VERSION 5.7 ;
BUSBITCHARS "[]" ;
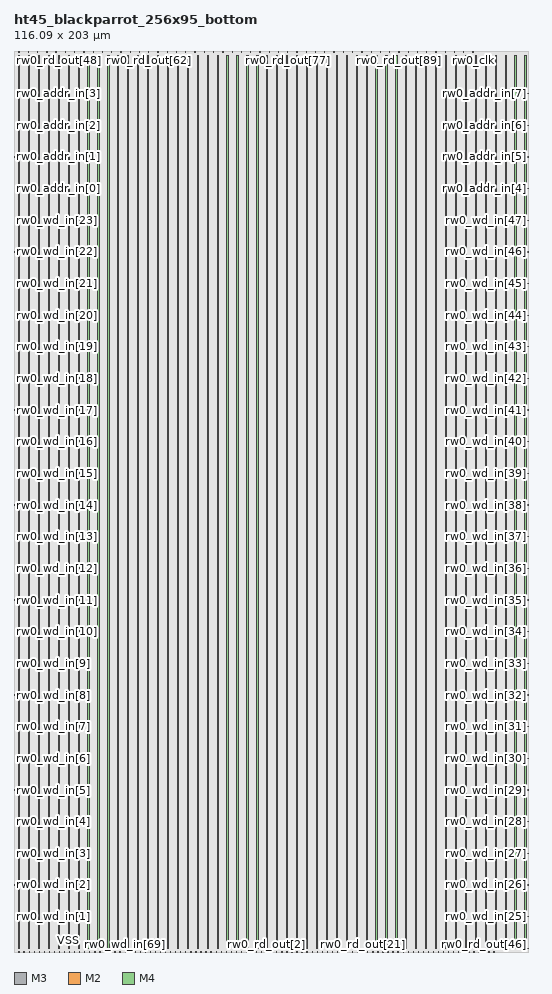
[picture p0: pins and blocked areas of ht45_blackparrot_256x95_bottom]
MACRO ht45_blackparrot_256x95_bottom
  FOREIGN ht45_blackparrot_256x95_bottom 0 0 ;
  SYMMETRY X Y R90 ;
  SIZE 116.090 BY 203.000 ;
  CLASS COVER ;
  PIN rw0_wd_in[0]
    DIRECTION INPUT ;
    USE SIGNAL ;
    SHAPE ABUTMENT ;
    PORT
      LAYER M3 ;
      RECT 0.000 0.805 0.210 0.875 ;
    END
  END rw0_wd_in[0]
  PIN rw0_wd_in[1]
    DIRECTION INPUT ;
    USE SIGNAL ;
    SHAPE ABUTMENT ;
    PORT
      LAYER M3 ;
      RECT 0.000 7.945 0.210 8.015 ;
    END
  END rw0_wd_in[1]
  PIN rw0_wd_in[2]
    DIRECTION INPUT ;
    USE SIGNAL ;
    SHAPE ABUTMENT ;
    PORT
      LAYER M3 ;
      RECT 0.000 15.085 0.210 15.155 ;
    END
  END rw0_wd_in[2]
  PIN rw0_wd_in[3]
    DIRECTION INPUT ;
    USE SIGNAL ;
    SHAPE ABUTMENT ;
    PORT
      LAYER M3 ;
      RECT 0.000 22.225 0.210 22.295 ;
    END
  END rw0_wd_in[3]
  PIN rw0_wd_in[4]
    DIRECTION INPUT ;
    USE SIGNAL ;
    SHAPE ABUTMENT ;
    PORT
      LAYER M3 ;
      RECT 0.000 29.365 0.210 29.435 ;
    END
  END rw0_wd_in[4]
  PIN rw0_wd_in[5]
    DIRECTION INPUT ;
    USE SIGNAL ;
    SHAPE ABUTMENT ;
    PORT
      LAYER M3 ;
      RECT 0.000 36.505 0.210 36.575 ;
    END
  END rw0_wd_in[5]
  PIN rw0_wd_in[6]
    DIRECTION INPUT ;
    USE SIGNAL ;
    SHAPE ABUTMENT ;
    PORT
      LAYER M3 ;
      RECT 0.000 43.645 0.210 43.715 ;
    END
  END rw0_wd_in[6]
  PIN rw0_wd_in[7]
    DIRECTION INPUT ;
    USE SIGNAL ;
    SHAPE ABUTMENT ;
    PORT
      LAYER M3 ;
      RECT 0.000 50.785 0.210 50.855 ;
    END
  END rw0_wd_in[7]
  PIN rw0_wd_in[8]
    DIRECTION INPUT ;
    USE SIGNAL ;
    SHAPE ABUTMENT ;
    PORT
      LAYER M3 ;
      RECT 0.000 57.925 0.210 57.995 ;
    END
  END rw0_wd_in[8]
  PIN rw0_wd_in[9]
    DIRECTION INPUT ;
    USE SIGNAL ;
    SHAPE ABUTMENT ;
    PORT
      LAYER M3 ;
      RECT 0.000 65.065 0.210 65.135 ;
    END
  END rw0_wd_in[9]
  PIN rw0_wd_in[10]
    DIRECTION INPUT ;
    USE SIGNAL ;
    SHAPE ABUTMENT ;
    PORT
      LAYER M3 ;
      RECT 0.000 72.205 0.210 72.275 ;
    END
  END rw0_wd_in[10]
  PIN rw0_wd_in[11]
    DIRECTION INPUT ;
    USE SIGNAL ;
    SHAPE ABUTMENT ;
    PORT
      LAYER M3 ;
      RECT 0.000 79.345 0.210 79.415 ;
    END
  END rw0_wd_in[11]
  PIN rw0_wd_in[12]
    DIRECTION INPUT ;
    USE SIGNAL ;
    SHAPE ABUTMENT ;
    PORT
      LAYER M3 ;
      RECT 0.000 86.485 0.210 86.555 ;
    END
  END rw0_wd_in[12]
  PIN rw0_wd_in[13]
    DIRECTION INPUT ;
    USE SIGNAL ;
    SHAPE ABUTMENT ;
    PORT
      LAYER M3 ;
      RECT 0.000 93.625 0.210 93.695 ;
    END
  END rw0_wd_in[13]
  PIN rw0_wd_in[14]
    DIRECTION INPUT ;
    USE SIGNAL ;
    SHAPE ABUTMENT ;
    PORT
      LAYER M3 ;
      RECT 0.000 100.765 0.210 100.835 ;
    END
  END rw0_wd_in[14]
  PIN rw0_wd_in[15]
    DIRECTION INPUT ;
    USE SIGNAL ;
    SHAPE ABUTMENT ;
    PORT
      LAYER M3 ;
      RECT 0.000 107.905 0.210 107.975 ;
    END
  END rw0_wd_in[15]
  PIN rw0_wd_in[16]
    DIRECTION INPUT ;
    USE SIGNAL ;
    SHAPE ABUTMENT ;
    PORT
      LAYER M3 ;
      RECT 0.000 115.045 0.210 115.115 ;
    END
  END rw0_wd_in[16]
  PIN rw0_wd_in[17]
    DIRECTION INPUT ;
    USE SIGNAL ;
    SHAPE ABUTMENT ;
    PORT
      LAYER M3 ;
      RECT 0.000 122.185 0.210 122.255 ;
    END
  END rw0_wd_in[17]
  PIN rw0_wd_in[18]
    DIRECTION INPUT ;
    USE SIGNAL ;
    SHAPE ABUTMENT ;
    PORT
      LAYER M3 ;
      RECT 0.000 129.325 0.210 129.395 ;
    END
  END rw0_wd_in[18]
  PIN rw0_wd_in[19]
    DIRECTION INPUT ;
    USE SIGNAL ;
    SHAPE ABUTMENT ;
    PORT
      LAYER M3 ;
      RECT 0.000 136.465 0.210 136.535 ;
    END
  END rw0_wd_in[19]
  PIN rw0_wd_in[20]
    DIRECTION INPUT ;
    USE SIGNAL ;
    SHAPE ABUTMENT ;
    PORT
      LAYER M3 ;
      RECT 0.000 143.605 0.210 143.675 ;
    END
  END rw0_wd_in[20]
  PIN rw0_wd_in[21]
    DIRECTION INPUT ;
    USE SIGNAL ;
    SHAPE ABUTMENT ;
    PORT
      LAYER M3 ;
      RECT 0.000 150.745 0.210 150.815 ;
    END
  END rw0_wd_in[21]
  PIN rw0_wd_in[22]
    DIRECTION INPUT ;
    USE SIGNAL ;
    SHAPE ABUTMENT ;
    PORT
      LAYER M3 ;
      RECT 0.000 157.885 0.210 157.955 ;
    END
  END rw0_wd_in[22]
  PIN rw0_wd_in[23]
    DIRECTION INPUT ;
    USE SIGNAL ;
    SHAPE ABUTMENT ;
    PORT
      LAYER M3 ;
      RECT 0.000 165.025 0.210 165.095 ;
    END
  END rw0_wd_in[23]
  PIN rw0_wd_in[24]
    DIRECTION INPUT ;
    USE SIGNAL ;
    SHAPE ABUTMENT ;
    PORT
      LAYER M3 ;
      RECT 115.880 0.805 116.090 0.875 ;
    END
  END rw0_wd_in[24]
  PIN rw0_wd_in[25]
    DIRECTION INPUT ;
    USE SIGNAL ;
    SHAPE ABUTMENT ;
    PORT
      LAYER M3 ;
      RECT 115.880 7.945 116.090 8.015 ;
    END
  END rw0_wd_in[25]
  PIN rw0_wd_in[26]
    DIRECTION INPUT ;
    USE SIGNAL ;
    SHAPE ABUTMENT ;
    PORT
      LAYER M3 ;
      RECT 115.880 15.085 116.090 15.155 ;
    END
  END rw0_wd_in[26]
  PIN rw0_wd_in[27]
    DIRECTION INPUT ;
    USE SIGNAL ;
    SHAPE ABUTMENT ;
    PORT
      LAYER M3 ;
      RECT 115.880 22.225 116.090 22.295 ;
    END
  END rw0_wd_in[27]
  PIN rw0_wd_in[28]
    DIRECTION INPUT ;
    USE SIGNAL ;
    SHAPE ABUTMENT ;
    PORT
      LAYER M3 ;
      RECT 115.880 29.365 116.090 29.435 ;
    END
  END rw0_wd_in[28]
  PIN rw0_wd_in[29]
    DIRECTION INPUT ;
    USE SIGNAL ;
    SHAPE ABUTMENT ;
    PORT
      LAYER M3 ;
      RECT 115.880 36.505 116.090 36.575 ;
    END
  END rw0_wd_in[29]
  PIN rw0_wd_in[30]
    DIRECTION INPUT ;
    USE SIGNAL ;
    SHAPE ABUTMENT ;
    PORT
      LAYER M3 ;
      RECT 115.880 43.645 116.090 43.715 ;
    END
  END rw0_wd_in[30]
  PIN rw0_wd_in[31]
    DIRECTION INPUT ;
    USE SIGNAL ;
    SHAPE ABUTMENT ;
    PORT
      LAYER M3 ;
      RECT 115.880 50.785 116.090 50.855 ;
    END
  END rw0_wd_in[31]
  PIN rw0_wd_in[32]
    DIRECTION INPUT ;
    USE SIGNAL ;
    SHAPE ABUTMENT ;
    PORT
      LAYER M3 ;
      RECT 115.880 57.925 116.090 57.995 ;
    END
  END rw0_wd_in[32]
  PIN rw0_wd_in[33]
    DIRECTION INPUT ;
    USE SIGNAL ;
    SHAPE ABUTMENT ;
    PORT
      LAYER M3 ;
      RECT 115.880 65.065 116.090 65.135 ;
    END
  END rw0_wd_in[33]
  PIN rw0_wd_in[34]
    DIRECTION INPUT ;
    USE SIGNAL ;
    SHAPE ABUTMENT ;
    PORT
      LAYER M3 ;
      RECT 115.880 72.205 116.090 72.275 ;
    END
  END rw0_wd_in[34]
  PIN rw0_wd_in[35]
    DIRECTION INPUT ;
    USE SIGNAL ;
    SHAPE ABUTMENT ;
    PORT
      LAYER M3 ;
      RECT 115.880 79.345 116.090 79.415 ;
    END
  END rw0_wd_in[35]
  PIN rw0_wd_in[36]
    DIRECTION INPUT ;
    USE SIGNAL ;
    SHAPE ABUTMENT ;
    PORT
      LAYER M3 ;
      RECT 115.880 86.485 116.090 86.555 ;
    END
  END rw0_wd_in[36]
  PIN rw0_wd_in[37]
    DIRECTION INPUT ;
    USE SIGNAL ;
    SHAPE ABUTMENT ;
    PORT
      LAYER M3 ;
      RECT 115.880 93.625 116.090 93.695 ;
    END
  END rw0_wd_in[37]
  PIN rw0_wd_in[38]
    DIRECTION INPUT ;
    USE SIGNAL ;
    SHAPE ABUTMENT ;
    PORT
      LAYER M3 ;
      RECT 115.880 100.765 116.090 100.835 ;
    END
  END rw0_wd_in[38]
  PIN rw0_wd_in[39]
    DIRECTION INPUT ;
    USE SIGNAL ;
    SHAPE ABUTMENT ;
    PORT
      LAYER M3 ;
      RECT 115.880 107.905 116.090 107.975 ;
    END
  END rw0_wd_in[39]
  PIN rw0_wd_in[40]
    DIRECTION INPUT ;
    USE SIGNAL ;
    SHAPE ABUTMENT ;
    PORT
      LAYER M3 ;
      RECT 115.880 115.045 116.090 115.115 ;
    END
  END rw0_wd_in[40]
  PIN rw0_wd_in[41]
    DIRECTION INPUT ;
    USE SIGNAL ;
    SHAPE ABUTMENT ;
    PORT
      LAYER M3 ;
      RECT 115.880 122.185 116.090 122.255 ;
    END
  END rw0_wd_in[41]
  PIN rw0_wd_in[42]
    DIRECTION INPUT ;
    USE SIGNAL ;
    SHAPE ABUTMENT ;
    PORT
      LAYER M3 ;
      RECT 115.880 129.325 116.090 129.395 ;
    END
  END rw0_wd_in[42]
  PIN rw0_wd_in[43]
    DIRECTION INPUT ;
    USE SIGNAL ;
    SHAPE ABUTMENT ;
    PORT
      LAYER M3 ;
      RECT 115.880 136.465 116.090 136.535 ;
    END
  END rw0_wd_in[43]
  PIN rw0_wd_in[44]
    DIRECTION INPUT ;
    USE SIGNAL ;
    SHAPE ABUTMENT ;
    PORT
      LAYER M3 ;
      RECT 115.880 143.605 116.090 143.675 ;
    END
  END rw0_wd_in[44]
  PIN rw0_wd_in[45]
    DIRECTION INPUT ;
    USE SIGNAL ;
    SHAPE ABUTMENT ;
    PORT
      LAYER M3 ;
      RECT 115.880 150.745 116.090 150.815 ;
    END
  END rw0_wd_in[45]
  PIN rw0_wd_in[46]
    DIRECTION INPUT ;
    USE SIGNAL ;
    SHAPE ABUTMENT ;
    PORT
      LAYER M3 ;
      RECT 115.880 157.885 116.090 157.955 ;
    END
  END rw0_wd_in[46]
  PIN rw0_wd_in[47]
    DIRECTION INPUT ;
    USE SIGNAL ;
    SHAPE ABUTMENT ;
    PORT
      LAYER M3 ;
      RECT 115.880 165.025 116.090 165.095 ;
    END
  END rw0_wd_in[47]
  PIN rw0_wd_in[48]
    DIRECTION INPUT ;
    USE SIGNAL ;
    SHAPE ABUTMENT ;
    PORT
      LAYER M2 ;
      RECT 1.105 0.000 1.175 0.210 ;
    END
  END rw0_wd_in[48]
  PIN rw0_wd_in[49]
    DIRECTION INPUT ;
    USE SIGNAL ;
    SHAPE ABUTMENT ;
    PORT
      LAYER M2 ;
      RECT 2.245 0.000 2.315 0.210 ;
    END
  END rw0_wd_in[49]
  PIN rw0_wd_in[50]
    DIRECTION INPUT ;
    USE SIGNAL ;
    SHAPE ABUTMENT ;
    PORT
      LAYER M2 ;
      RECT 3.385 0.000 3.455 0.210 ;
    END
  END rw0_wd_in[50]
  PIN rw0_wd_in[51]
    DIRECTION INPUT ;
    USE SIGNAL ;
    SHAPE ABUTMENT ;
    PORT
      LAYER M2 ;
      RECT 4.525 0.000 4.595 0.210 ;
    END
  END rw0_wd_in[51]
  PIN rw0_wd_in[52]
    DIRECTION INPUT ;
    USE SIGNAL ;
    SHAPE ABUTMENT ;
    PORT
      LAYER M2 ;
      RECT 5.665 0.000 5.735 0.210 ;
    END
  END rw0_wd_in[52]
  PIN rw0_wd_in[53]
    DIRECTION INPUT ;
    USE SIGNAL ;
    SHAPE ABUTMENT ;
    PORT
      LAYER M2 ;
      RECT 6.805 0.000 6.875 0.210 ;
    END
  END rw0_wd_in[53]
  PIN rw0_wd_in[54]
    DIRECTION INPUT ;
    USE SIGNAL ;
    SHAPE ABUTMENT ;
    PORT
      LAYER M2 ;
      RECT 7.945 0.000 8.015 0.210 ;
    END
  END rw0_wd_in[54]
  PIN rw0_wd_in[55]
    DIRECTION INPUT ;
    USE SIGNAL ;
    SHAPE ABUTMENT ;
    PORT
      LAYER M2 ;
      RECT 9.085 0.000 9.155 0.210 ;
    END
  END rw0_wd_in[55]
  PIN rw0_wd_in[56]
    DIRECTION INPUT ;
    USE SIGNAL ;
    SHAPE ABUTMENT ;
    PORT
      LAYER M2 ;
      RECT 10.225 0.000 10.295 0.210 ;
    END
  END rw0_wd_in[56]
  PIN rw0_wd_in[57]
    DIRECTION INPUT ;
    USE SIGNAL ;
    SHAPE ABUTMENT ;
    PORT
      LAYER M2 ;
      RECT 11.365 0.000 11.435 0.210 ;
    END
  END rw0_wd_in[57]
  PIN rw0_wd_in[58]
    DIRECTION INPUT ;
    USE SIGNAL ;
    SHAPE ABUTMENT ;
    PORT
      LAYER M2 ;
      RECT 12.505 0.000 12.575 0.210 ;
    END
  END rw0_wd_in[58]
  PIN rw0_wd_in[59]
    DIRECTION INPUT ;
    USE SIGNAL ;
    SHAPE ABUTMENT ;
    PORT
      LAYER M2 ;
      RECT 13.645 0.000 13.715 0.210 ;
    END
  END rw0_wd_in[59]
  PIN rw0_wd_in[60]
    DIRECTION INPUT ;
    USE SIGNAL ;
    SHAPE ABUTMENT ;
    PORT
      LAYER M2 ;
      RECT 14.785 0.000 14.855 0.210 ;
    END
  END rw0_wd_in[60]
  PIN rw0_wd_in[61]
    DIRECTION INPUT ;
    USE SIGNAL ;
    SHAPE ABUTMENT ;
    PORT
      LAYER M2 ;
      RECT 15.925 0.000 15.995 0.210 ;
    END
  END rw0_wd_in[61]
  PIN rw0_wd_in[62]
    DIRECTION INPUT ;
    USE SIGNAL ;
    SHAPE ABUTMENT ;
    PORT
      LAYER M2 ;
      RECT 17.065 0.000 17.135 0.210 ;
    END
  END rw0_wd_in[62]
  PIN rw0_wd_in[63]
    DIRECTION INPUT ;
    USE SIGNAL ;
    SHAPE ABUTMENT ;
    PORT
      LAYER M2 ;
      RECT 18.205 0.000 18.275 0.210 ;
    END
  END rw0_wd_in[63]
  PIN rw0_wd_in[64]
    DIRECTION INPUT ;
    USE SIGNAL ;
    SHAPE ABUTMENT ;
    PORT
      LAYER M2 ;
      RECT 19.345 0.000 19.415 0.210 ;
    END
  END rw0_wd_in[64]
  PIN rw0_wd_in[65]
    DIRECTION INPUT ;
    USE SIGNAL ;
    SHAPE ABUTMENT ;
    PORT
      LAYER M2 ;
      RECT 20.485 0.000 20.555 0.210 ;
    END
  END rw0_wd_in[65]
  PIN rw0_wd_in[66]
    DIRECTION INPUT ;
    USE SIGNAL ;
    SHAPE ABUTMENT ;
    PORT
      LAYER M2 ;
      RECT 21.625 0.000 21.695 0.210 ;
    END
  END rw0_wd_in[66]
  PIN rw0_wd_in[67]
    DIRECTION INPUT ;
    USE SIGNAL ;
    SHAPE ABUTMENT ;
    PORT
      LAYER M2 ;
      RECT 22.765 0.000 22.835 0.210 ;
    END
  END rw0_wd_in[67]
  PIN rw0_wd_in[68]
    DIRECTION INPUT ;
    USE SIGNAL ;
    SHAPE ABUTMENT ;
    PORT
      LAYER M2 ;
      RECT 23.905 0.000 23.975 0.210 ;
    END
  END rw0_wd_in[68]
  PIN rw0_wd_in[69]
    DIRECTION INPUT ;
    USE SIGNAL ;
    SHAPE ABUTMENT ;
    PORT
      LAYER M2 ;
      RECT 25.045 0.000 25.115 0.210 ;
    END
  END rw0_wd_in[69]
  PIN rw0_wd_in[70]
    DIRECTION INPUT ;
    USE SIGNAL ;
    SHAPE ABUTMENT ;
    PORT
      LAYER M2 ;
      RECT 26.185 0.000 26.255 0.210 ;
    END
  END rw0_wd_in[70]
  PIN rw0_wd_in[71]
    DIRECTION INPUT ;
    USE SIGNAL ;
    SHAPE ABUTMENT ;
    PORT
      LAYER M2 ;
      RECT 27.325 0.000 27.395 0.210 ;
    END
  END rw0_wd_in[71]
  PIN rw0_wd_in[72]
    DIRECTION INPUT ;
    USE SIGNAL ;
    SHAPE ABUTMENT ;
    PORT
      LAYER M2 ;
      RECT 28.465 0.000 28.535 0.210 ;
    END
  END rw0_wd_in[72]
  PIN rw0_wd_in[73]
    DIRECTION INPUT ;
    USE SIGNAL ;
    SHAPE ABUTMENT ;
    PORT
      LAYER M2 ;
      RECT 29.605 0.000 29.675 0.210 ;
    END
  END rw0_wd_in[73]
  PIN rw0_wd_in[74]
    DIRECTION INPUT ;
    USE SIGNAL ;
    SHAPE ABUTMENT ;
    PORT
      LAYER M2 ;
      RECT 30.745 0.000 30.815 0.210 ;
    END
  END rw0_wd_in[74]
  PIN rw0_wd_in[75]
    DIRECTION INPUT ;
    USE SIGNAL ;
    SHAPE ABUTMENT ;
    PORT
      LAYER M2 ;
      RECT 31.885 0.000 31.955 0.210 ;
    END
  END rw0_wd_in[75]
  PIN rw0_wd_in[76]
    DIRECTION INPUT ;
    USE SIGNAL ;
    SHAPE ABUTMENT ;
    PORT
      LAYER M2 ;
      RECT 33.025 0.000 33.095 0.210 ;
    END
  END rw0_wd_in[76]
  PIN rw0_wd_in[77]
    DIRECTION INPUT ;
    USE SIGNAL ;
    SHAPE ABUTMENT ;
    PORT
      LAYER M2 ;
      RECT 34.165 0.000 34.235 0.210 ;
    END
  END rw0_wd_in[77]
  PIN rw0_wd_in[78]
    DIRECTION INPUT ;
    USE SIGNAL ;
    SHAPE ABUTMENT ;
    PORT
      LAYER M2 ;
      RECT 35.305 0.000 35.375 0.210 ;
    END
  END rw0_wd_in[78]
  PIN rw0_wd_in[79]
    DIRECTION INPUT ;
    USE SIGNAL ;
    SHAPE ABUTMENT ;
    PORT
      LAYER M2 ;
      RECT 36.445 0.000 36.515 0.210 ;
    END
  END rw0_wd_in[79]
  PIN rw0_wd_in[80]
    DIRECTION INPUT ;
    USE SIGNAL ;
    SHAPE ABUTMENT ;
    PORT
      LAYER M2 ;
      RECT 37.585 0.000 37.655 0.210 ;
    END
  END rw0_wd_in[80]
  PIN rw0_wd_in[81]
    DIRECTION INPUT ;
    USE SIGNAL ;
    SHAPE ABUTMENT ;
    PORT
      LAYER M2 ;
      RECT 38.725 0.000 38.795 0.210 ;
    END
  END rw0_wd_in[81]
  PIN rw0_wd_in[82]
    DIRECTION INPUT ;
    USE SIGNAL ;
    SHAPE ABUTMENT ;
    PORT
      LAYER M2 ;
      RECT 39.865 0.000 39.935 0.210 ;
    END
  END rw0_wd_in[82]
  PIN rw0_wd_in[83]
    DIRECTION INPUT ;
    USE SIGNAL ;
    SHAPE ABUTMENT ;
    PORT
      LAYER M2 ;
      RECT 41.005 0.000 41.075 0.210 ;
    END
  END rw0_wd_in[83]
  PIN rw0_wd_in[84]
    DIRECTION INPUT ;
    USE SIGNAL ;
    SHAPE ABUTMENT ;
    PORT
      LAYER M2 ;
      RECT 42.145 0.000 42.215 0.210 ;
    END
  END rw0_wd_in[84]
  PIN rw0_wd_in[85]
    DIRECTION INPUT ;
    USE SIGNAL ;
    SHAPE ABUTMENT ;
    PORT
      LAYER M2 ;
      RECT 43.285 0.000 43.355 0.210 ;
    END
  END rw0_wd_in[85]
  PIN rw0_wd_in[86]
    DIRECTION INPUT ;
    USE SIGNAL ;
    SHAPE ABUTMENT ;
    PORT
      LAYER M2 ;
      RECT 44.425 0.000 44.495 0.210 ;
    END
  END rw0_wd_in[86]
  PIN rw0_wd_in[87]
    DIRECTION INPUT ;
    USE SIGNAL ;
    SHAPE ABUTMENT ;
    PORT
      LAYER M2 ;
      RECT 45.565 0.000 45.635 0.210 ;
    END
  END rw0_wd_in[87]
  PIN rw0_wd_in[88]
    DIRECTION INPUT ;
    USE SIGNAL ;
    SHAPE ABUTMENT ;
    PORT
      LAYER M2 ;
      RECT 46.705 0.000 46.775 0.210 ;
    END
  END rw0_wd_in[88]
  PIN rw0_wd_in[89]
    DIRECTION INPUT ;
    USE SIGNAL ;
    SHAPE ABUTMENT ;
    PORT
      LAYER M2 ;
      RECT 47.845 0.000 47.915 0.210 ;
    END
  END rw0_wd_in[89]
  PIN rw0_wd_in[90]
    DIRECTION INPUT ;
    USE SIGNAL ;
    SHAPE ABUTMENT ;
    PORT
      LAYER M2 ;
      RECT 48.985 0.000 49.055 0.210 ;
    END
  END rw0_wd_in[90]
  PIN rw0_wd_in[91]
    DIRECTION INPUT ;
    USE SIGNAL ;
    SHAPE ABUTMENT ;
    PORT
      LAYER M2 ;
      RECT 50.125 0.000 50.195 0.210 ;
    END
  END rw0_wd_in[91]
  PIN rw0_wd_in[92]
    DIRECTION INPUT ;
    USE SIGNAL ;
    SHAPE ABUTMENT ;
    PORT
      LAYER M2 ;
      RECT 51.265 0.000 51.335 0.210 ;
    END
  END rw0_wd_in[92]
  PIN rw0_wd_in[93]
    DIRECTION INPUT ;
    USE SIGNAL ;
    SHAPE ABUTMENT ;
    PORT
      LAYER M2 ;
      RECT 52.405 0.000 52.475 0.210 ;
    END
  END rw0_wd_in[93]
  PIN rw0_wd_in[94]
    DIRECTION INPUT ;
    USE SIGNAL ;
    SHAPE ABUTMENT ;
    PORT
      LAYER M2 ;
      RECT 53.545 0.000 53.615 0.210 ;
    END
  END rw0_wd_in[94]
  PIN rw0_rd_out[0]
    DIRECTION OUTPUT ;
    USE SIGNAL ;
    SHAPE ABUTMENT ;
    PORT
      LAYER M2 ;
      RECT 54.685 0.000 54.755 0.210 ;
    END
  END rw0_rd_out[0]
  PIN rw0_rd_out[1]
    DIRECTION OUTPUT ;
    USE SIGNAL ;
    SHAPE ABUTMENT ;
    PORT
      LAYER M2 ;
      RECT 55.825 0.000 55.895 0.210 ;
    END
  END rw0_rd_out[1]
  PIN rw0_rd_out[2]
    DIRECTION OUTPUT ;
    USE SIGNAL ;
    SHAPE ABUTMENT ;
    PORT
      LAYER M2 ;
      RECT 56.965 0.000 57.035 0.210 ;
    END
  END rw0_rd_out[2]
  PIN rw0_rd_out[3]
    DIRECTION OUTPUT ;
    USE SIGNAL ;
    SHAPE ABUTMENT ;
    PORT
      LAYER M2 ;
      RECT 58.105 0.000 58.175 0.210 ;
    END
  END rw0_rd_out[3]
  PIN rw0_rd_out[4]
    DIRECTION OUTPUT ;
    USE SIGNAL ;
    SHAPE ABUTMENT ;
    PORT
      LAYER M2 ;
      RECT 59.245 0.000 59.315 0.210 ;
    END
  END rw0_rd_out[4]
  PIN rw0_rd_out[5]
    DIRECTION OUTPUT ;
    USE SIGNAL ;
    SHAPE ABUTMENT ;
    PORT
      LAYER M2 ;
      RECT 60.385 0.000 60.455 0.210 ;
    END
  END rw0_rd_out[5]
  PIN rw0_rd_out[6]
    DIRECTION OUTPUT ;
    USE SIGNAL ;
    SHAPE ABUTMENT ;
    PORT
      LAYER M2 ;
      RECT 61.525 0.000 61.595 0.210 ;
    END
  END rw0_rd_out[6]
  PIN rw0_rd_out[7]
    DIRECTION OUTPUT ;
    USE SIGNAL ;
    SHAPE ABUTMENT ;
    PORT
      LAYER M2 ;
      RECT 62.665 0.000 62.735 0.210 ;
    END
  END rw0_rd_out[7]
  PIN rw0_rd_out[8]
    DIRECTION OUTPUT ;
    USE SIGNAL ;
    SHAPE ABUTMENT ;
    PORT
      LAYER M2 ;
      RECT 63.805 0.000 63.875 0.210 ;
    END
  END rw0_rd_out[8]
  PIN rw0_rd_out[9]
    DIRECTION OUTPUT ;
    USE SIGNAL ;
    SHAPE ABUTMENT ;
    PORT
      LAYER M2 ;
      RECT 64.945 0.000 65.015 0.210 ;
    END
  END rw0_rd_out[9]
  PIN rw0_rd_out[10]
    DIRECTION OUTPUT ;
    USE SIGNAL ;
    SHAPE ABUTMENT ;
    PORT
      LAYER M2 ;
      RECT 66.085 0.000 66.155 0.210 ;
    END
  END rw0_rd_out[10]
  PIN rw0_rd_out[11]
    DIRECTION OUTPUT ;
    USE SIGNAL ;
    SHAPE ABUTMENT ;
    PORT
      LAYER M2 ;
      RECT 67.225 0.000 67.295 0.210 ;
    END
  END rw0_rd_out[11]
  PIN rw0_rd_out[12]
    DIRECTION OUTPUT ;
    USE SIGNAL ;
    SHAPE ABUTMENT ;
    PORT
      LAYER M2 ;
      RECT 68.365 0.000 68.435 0.210 ;
    END
  END rw0_rd_out[12]
  PIN rw0_rd_out[13]
    DIRECTION OUTPUT ;
    USE SIGNAL ;
    SHAPE ABUTMENT ;
    PORT
      LAYER M2 ;
      RECT 69.505 0.000 69.575 0.210 ;
    END
  END rw0_rd_out[13]
  PIN rw0_rd_out[14]
    DIRECTION OUTPUT ;
    USE SIGNAL ;
    SHAPE ABUTMENT ;
    PORT
      LAYER M2 ;
      RECT 70.645 0.000 70.715 0.210 ;
    END
  END rw0_rd_out[14]
  PIN rw0_rd_out[15]
    DIRECTION OUTPUT ;
    USE SIGNAL ;
    SHAPE ABUTMENT ;
    PORT
      LAYER M2 ;
      RECT 71.785 0.000 71.855 0.210 ;
    END
  END rw0_rd_out[15]
  PIN rw0_rd_out[16]
    DIRECTION OUTPUT ;
    USE SIGNAL ;
    SHAPE ABUTMENT ;
    PORT
      LAYER M2 ;
      RECT 72.925 0.000 72.995 0.210 ;
    END
  END rw0_rd_out[16]
  PIN rw0_rd_out[17]
    DIRECTION OUTPUT ;
    USE SIGNAL ;
    SHAPE ABUTMENT ;
    PORT
      LAYER M2 ;
      RECT 74.065 0.000 74.135 0.210 ;
    END
  END rw0_rd_out[17]
  PIN rw0_rd_out[18]
    DIRECTION OUTPUT ;
    USE SIGNAL ;
    SHAPE ABUTMENT ;
    PORT
      LAYER M2 ;
      RECT 75.205 0.000 75.275 0.210 ;
    END
  END rw0_rd_out[18]
  PIN rw0_rd_out[19]
    DIRECTION OUTPUT ;
    USE SIGNAL ;
    SHAPE ABUTMENT ;
    PORT
      LAYER M2 ;
      RECT 76.345 0.000 76.415 0.210 ;
    END
  END rw0_rd_out[19]
  PIN rw0_rd_out[20]
    DIRECTION OUTPUT ;
    USE SIGNAL ;
    SHAPE ABUTMENT ;
    PORT
      LAYER M2 ;
      RECT 77.485 0.000 77.555 0.210 ;
    END
  END rw0_rd_out[20]
  PIN rw0_rd_out[21]
    DIRECTION OUTPUT ;
    USE SIGNAL ;
    SHAPE ABUTMENT ;
    PORT
      LAYER M2 ;
      RECT 78.625 0.000 78.695 0.210 ;
    END
  END rw0_rd_out[21]
  PIN rw0_rd_out[22]
    DIRECTION OUTPUT ;
    USE SIGNAL ;
    SHAPE ABUTMENT ;
    PORT
      LAYER M2 ;
      RECT 79.765 0.000 79.835 0.210 ;
    END
  END rw0_rd_out[22]
  PIN rw0_rd_out[23]
    DIRECTION OUTPUT ;
    USE SIGNAL ;
    SHAPE ABUTMENT ;
    PORT
      LAYER M2 ;
      RECT 80.905 0.000 80.975 0.210 ;
    END
  END rw0_rd_out[23]
  PIN rw0_rd_out[24]
    DIRECTION OUTPUT ;
    USE SIGNAL ;
    SHAPE ABUTMENT ;
    PORT
      LAYER M2 ;
      RECT 82.045 0.000 82.115 0.210 ;
    END
  END rw0_rd_out[24]
  PIN rw0_rd_out[25]
    DIRECTION OUTPUT ;
    USE SIGNAL ;
    SHAPE ABUTMENT ;
    PORT
      LAYER M2 ;
      RECT 83.185 0.000 83.255 0.210 ;
    END
  END rw0_rd_out[25]
  PIN rw0_rd_out[26]
    DIRECTION OUTPUT ;
    USE SIGNAL ;
    SHAPE ABUTMENT ;
    PORT
      LAYER M2 ;
      RECT 84.325 0.000 84.395 0.210 ;
    END
  END rw0_rd_out[26]
  PIN rw0_rd_out[27]
    DIRECTION OUTPUT ;
    USE SIGNAL ;
    SHAPE ABUTMENT ;
    PORT
      LAYER M2 ;
      RECT 85.465 0.000 85.535 0.210 ;
    END
  END rw0_rd_out[27]
  PIN rw0_rd_out[28]
    DIRECTION OUTPUT ;
    USE SIGNAL ;
    SHAPE ABUTMENT ;
    PORT
      LAYER M2 ;
      RECT 86.605 0.000 86.675 0.210 ;
    END
  END rw0_rd_out[28]
  PIN rw0_rd_out[29]
    DIRECTION OUTPUT ;
    USE SIGNAL ;
    SHAPE ABUTMENT ;
    PORT
      LAYER M2 ;
      RECT 87.745 0.000 87.815 0.210 ;
    END
  END rw0_rd_out[29]
  PIN rw0_rd_out[30]
    DIRECTION OUTPUT ;
    USE SIGNAL ;
    SHAPE ABUTMENT ;
    PORT
      LAYER M2 ;
      RECT 88.885 0.000 88.955 0.210 ;
    END
  END rw0_rd_out[30]
  PIN rw0_rd_out[31]
    DIRECTION OUTPUT ;
    USE SIGNAL ;
    SHAPE ABUTMENT ;
    PORT
      LAYER M2 ;
      RECT 90.025 0.000 90.095 0.210 ;
    END
  END rw0_rd_out[31]
  PIN rw0_rd_out[32]
    DIRECTION OUTPUT ;
    USE SIGNAL ;
    SHAPE ABUTMENT ;
    PORT
      LAYER M2 ;
      RECT 91.165 0.000 91.235 0.210 ;
    END
  END rw0_rd_out[32]
  PIN rw0_rd_out[33]
    DIRECTION OUTPUT ;
    USE SIGNAL ;
    SHAPE ABUTMENT ;
    PORT
      LAYER M2 ;
      RECT 92.305 0.000 92.375 0.210 ;
    END
  END rw0_rd_out[33]
  PIN rw0_rd_out[34]
    DIRECTION OUTPUT ;
    USE SIGNAL ;
    SHAPE ABUTMENT ;
    PORT
      LAYER M2 ;
      RECT 93.445 0.000 93.515 0.210 ;
    END
  END rw0_rd_out[34]
  PIN rw0_rd_out[35]
    DIRECTION OUTPUT ;
    USE SIGNAL ;
    SHAPE ABUTMENT ;
    PORT
      LAYER M2 ;
      RECT 94.585 0.000 94.655 0.210 ;
    END
  END rw0_rd_out[35]
  PIN rw0_rd_out[36]
    DIRECTION OUTPUT ;
    USE SIGNAL ;
    SHAPE ABUTMENT ;
    PORT
      LAYER M2 ;
      RECT 95.725 0.000 95.795 0.210 ;
    END
  END rw0_rd_out[36]
  PIN rw0_rd_out[37]
    DIRECTION OUTPUT ;
    USE SIGNAL ;
    SHAPE ABUTMENT ;
    PORT
      LAYER M2 ;
      RECT 96.865 0.000 96.935 0.210 ;
    END
  END rw0_rd_out[37]
  PIN rw0_rd_out[38]
    DIRECTION OUTPUT ;
    USE SIGNAL ;
    SHAPE ABUTMENT ;
    PORT
      LAYER M2 ;
      RECT 98.005 0.000 98.075 0.210 ;
    END
  END rw0_rd_out[38]
  PIN rw0_rd_out[39]
    DIRECTION OUTPUT ;
    USE SIGNAL ;
    SHAPE ABUTMENT ;
    PORT
      LAYER M2 ;
      RECT 99.145 0.000 99.215 0.210 ;
    END
  END rw0_rd_out[39]
  PIN rw0_rd_out[40]
    DIRECTION OUTPUT ;
    USE SIGNAL ;
    SHAPE ABUTMENT ;
    PORT
      LAYER M2 ;
      RECT 100.285 0.000 100.355 0.210 ;
    END
  END rw0_rd_out[40]
  PIN rw0_rd_out[41]
    DIRECTION OUTPUT ;
    USE SIGNAL ;
    SHAPE ABUTMENT ;
    PORT
      LAYER M2 ;
      RECT 101.425 0.000 101.495 0.210 ;
    END
  END rw0_rd_out[41]
  PIN rw0_rd_out[42]
    DIRECTION OUTPUT ;
    USE SIGNAL ;
    SHAPE ABUTMENT ;
    PORT
      LAYER M2 ;
      RECT 102.565 0.000 102.635 0.210 ;
    END
  END rw0_rd_out[42]
  PIN rw0_rd_out[43]
    DIRECTION OUTPUT ;
    USE SIGNAL ;
    SHAPE ABUTMENT ;
    PORT
      LAYER M2 ;
      RECT 103.705 0.000 103.775 0.210 ;
    END
  END rw0_rd_out[43]
  PIN rw0_rd_out[44]
    DIRECTION OUTPUT ;
    USE SIGNAL ;
    SHAPE ABUTMENT ;
    PORT
      LAYER M2 ;
      RECT 104.845 0.000 104.915 0.210 ;
    END
  END rw0_rd_out[44]
  PIN rw0_rd_out[45]
    DIRECTION OUTPUT ;
    USE SIGNAL ;
    SHAPE ABUTMENT ;
    PORT
      LAYER M2 ;
      RECT 105.985 0.000 106.055 0.210 ;
    END
  END rw0_rd_out[45]
  PIN rw0_rd_out[46]
    DIRECTION OUTPUT ;
    USE SIGNAL ;
    SHAPE ABUTMENT ;
    PORT
      LAYER M2 ;
      RECT 107.125 0.000 107.195 0.210 ;
    END
  END rw0_rd_out[46]
  PIN rw0_rd_out[47]
    DIRECTION OUTPUT ;
    USE SIGNAL ;
    SHAPE ABUTMENT ;
    PORT
      LAYER M2 ;
      RECT 108.265 0.000 108.335 0.210 ;
    END
  END rw0_rd_out[47]
  PIN rw0_rd_out[48]
    DIRECTION OUTPUT ;
    USE SIGNAL ;
    SHAPE ABUTMENT ;
    PORT
      LAYER M2 ;
      RECT 1.105 202.790 1.175 203.000 ;
    END
  END rw0_rd_out[48]
  PIN rw0_rd_out[49]
    DIRECTION OUTPUT ;
    USE SIGNAL ;
    SHAPE ABUTMENT ;
    PORT
      LAYER M2 ;
      RECT 3.195 202.790 3.265 203.000 ;
    END
  END rw0_rd_out[49]
  PIN rw0_rd_out[50]
    DIRECTION OUTPUT ;
    USE SIGNAL ;
    SHAPE ABUTMENT ;
    PORT
      LAYER M2 ;
      RECT 5.285 202.790 5.355 203.000 ;
    END
  END rw0_rd_out[50]
  PIN rw0_rd_out[51]
    DIRECTION OUTPUT ;
    USE SIGNAL ;
    SHAPE ABUTMENT ;
    PORT
      LAYER M2 ;
      RECT 7.375 202.790 7.445 203.000 ;
    END
  END rw0_rd_out[51]
  PIN rw0_rd_out[52]
    DIRECTION OUTPUT ;
    USE SIGNAL ;
    SHAPE ABUTMENT ;
    PORT
      LAYER M2 ;
      RECT 9.465 202.790 9.535 203.000 ;
    END
  END rw0_rd_out[52]
  PIN rw0_rd_out[53]
    DIRECTION OUTPUT ;
    USE SIGNAL ;
    SHAPE ABUTMENT ;
    PORT
      LAYER M2 ;
      RECT 11.555 202.790 11.625 203.000 ;
    END
  END rw0_rd_out[53]
  PIN rw0_rd_out[54]
    DIRECTION OUTPUT ;
    USE SIGNAL ;
    SHAPE ABUTMENT ;
    PORT
      LAYER M2 ;
      RECT 13.645 202.790 13.715 203.000 ;
    END
  END rw0_rd_out[54]
  PIN rw0_rd_out[55]
    DIRECTION OUTPUT ;
    USE SIGNAL ;
    SHAPE ABUTMENT ;
    PORT
      LAYER M2 ;
      RECT 15.735 202.790 15.805 203.000 ;
    END
  END rw0_rd_out[55]
  PIN rw0_rd_out[56]
    DIRECTION OUTPUT ;
    USE SIGNAL ;
    SHAPE ABUTMENT ;
    PORT
      LAYER M2 ;
      RECT 17.825 202.790 17.895 203.000 ;
    END
  END rw0_rd_out[56]
  PIN rw0_rd_out[57]
    DIRECTION OUTPUT ;
    USE SIGNAL ;
    SHAPE ABUTMENT ;
    PORT
      LAYER M2 ;
      RECT 19.915 202.790 19.985 203.000 ;
    END
  END rw0_rd_out[57]
  PIN rw0_rd_out[58]
    DIRECTION OUTPUT ;
    USE SIGNAL ;
    SHAPE ABUTMENT ;
    PORT
      LAYER M2 ;
      RECT 22.005 202.790 22.075 203.000 ;
    END
  END rw0_rd_out[58]
  PIN rw0_rd_out[59]
    DIRECTION OUTPUT ;
    USE SIGNAL ;
    SHAPE ABUTMENT ;
    PORT
      LAYER M2 ;
      RECT 24.095 202.790 24.165 203.000 ;
    END
  END rw0_rd_out[59]
  PIN rw0_rd_out[60]
    DIRECTION OUTPUT ;
    USE SIGNAL ;
    SHAPE ABUTMENT ;
    PORT
      LAYER M2 ;
      RECT 26.185 202.790 26.255 203.000 ;
    END
  END rw0_rd_out[60]
  PIN rw0_rd_out[61]
    DIRECTION OUTPUT ;
    USE SIGNAL ;
    SHAPE ABUTMENT ;
    PORT
      LAYER M2 ;
      RECT 28.275 202.790 28.345 203.000 ;
    END
  END rw0_rd_out[61]
  PIN rw0_rd_out[62]
    DIRECTION OUTPUT ;
    USE SIGNAL ;
    SHAPE ABUTMENT ;
    PORT
      LAYER M2 ;
      RECT 30.365 202.790 30.435 203.000 ;
    END
  END rw0_rd_out[62]
  PIN rw0_rd_out[63]
    DIRECTION OUTPUT ;
    USE SIGNAL ;
    SHAPE ABUTMENT ;
    PORT
      LAYER M2 ;
      RECT 32.455 202.790 32.525 203.000 ;
    END
  END rw0_rd_out[63]
  PIN rw0_rd_out[64]
    DIRECTION OUTPUT ;
    USE SIGNAL ;
    SHAPE ABUTMENT ;
    PORT
      LAYER M2 ;
      RECT 34.545 202.790 34.615 203.000 ;
    END
  END rw0_rd_out[64]
  PIN rw0_rd_out[65]
    DIRECTION OUTPUT ;
    USE SIGNAL ;
    SHAPE ABUTMENT ;
    PORT
      LAYER M2 ;
      RECT 36.635 202.790 36.705 203.000 ;
    END
  END rw0_rd_out[65]
  PIN rw0_rd_out[66]
    DIRECTION OUTPUT ;
    USE SIGNAL ;
    SHAPE ABUTMENT ;
    PORT
      LAYER M2 ;
      RECT 38.725 202.790 38.795 203.000 ;
    END
  END rw0_rd_out[66]
  PIN rw0_rd_out[67]
    DIRECTION OUTPUT ;
    USE SIGNAL ;
    SHAPE ABUTMENT ;
    PORT
      LAYER M2 ;
      RECT 40.815 202.790 40.885 203.000 ;
    END
  END rw0_rd_out[67]
  PIN rw0_rd_out[68]
    DIRECTION OUTPUT ;
    USE SIGNAL ;
    SHAPE ABUTMENT ;
    PORT
      LAYER M2 ;
      RECT 42.905 202.790 42.975 203.000 ;
    END
  END rw0_rd_out[68]
  PIN rw0_rd_out[69]
    DIRECTION OUTPUT ;
    USE SIGNAL ;
    SHAPE ABUTMENT ;
    PORT
      LAYER M2 ;
      RECT 44.995 202.790 45.065 203.000 ;
    END
  END rw0_rd_out[69]
  PIN rw0_rd_out[70]
    DIRECTION OUTPUT ;
    USE SIGNAL ;
    SHAPE ABUTMENT ;
    PORT
      LAYER M2 ;
      RECT 47.085 202.790 47.155 203.000 ;
    END
  END rw0_rd_out[70]
  PIN rw0_rd_out[71]
    DIRECTION OUTPUT ;
    USE SIGNAL ;
    SHAPE ABUTMENT ;
    PORT
      LAYER M2 ;
      RECT 49.175 202.790 49.245 203.000 ;
    END
  END rw0_rd_out[71]
  PIN rw0_rd_out[72]
    DIRECTION OUTPUT ;
    USE SIGNAL ;
    SHAPE ABUTMENT ;
    PORT
      LAYER M2 ;
      RECT 51.265 202.790 51.335 203.000 ;
    END
  END rw0_rd_out[72]
  PIN rw0_rd_out[73]
    DIRECTION OUTPUT ;
    USE SIGNAL ;
    SHAPE ABUTMENT ;
    PORT
      LAYER M2 ;
      RECT 53.355 202.790 53.425 203.000 ;
    END
  END rw0_rd_out[73]
  PIN rw0_rd_out[74]
    DIRECTION OUTPUT ;
    USE SIGNAL ;
    SHAPE ABUTMENT ;
    PORT
      LAYER M2 ;
      RECT 55.445 202.790 55.515 203.000 ;
    END
  END rw0_rd_out[74]
  PIN rw0_rd_out[75]
    DIRECTION OUTPUT ;
    USE SIGNAL ;
    SHAPE ABUTMENT ;
    PORT
      LAYER M2 ;
      RECT 57.535 202.790 57.605 203.000 ;
    END
  END rw0_rd_out[75]
  PIN rw0_rd_out[76]
    DIRECTION OUTPUT ;
    USE SIGNAL ;
    SHAPE ABUTMENT ;
    PORT
      LAYER M2 ;
      RECT 59.625 202.790 59.695 203.000 ;
    END
  END rw0_rd_out[76]
  PIN rw0_rd_out[77]
    DIRECTION OUTPUT ;
    USE SIGNAL ;
    SHAPE ABUTMENT ;
    PORT
      LAYER M2 ;
      RECT 61.715 202.790 61.785 203.000 ;
    END
  END rw0_rd_out[77]
  PIN rw0_rd_out[78]
    DIRECTION OUTPUT ;
    USE SIGNAL ;
    SHAPE ABUTMENT ;
    PORT
      LAYER M2 ;
      RECT 63.805 202.790 63.875 203.000 ;
    END
  END rw0_rd_out[78]
  PIN rw0_rd_out[79]
    DIRECTION OUTPUT ;
    USE SIGNAL ;
    SHAPE ABUTMENT ;
    PORT
      LAYER M2 ;
      RECT 65.895 202.790 65.965 203.000 ;
    END
  END rw0_rd_out[79]
  PIN rw0_rd_out[80]
    DIRECTION OUTPUT ;
    USE SIGNAL ;
    SHAPE ABUTMENT ;
    PORT
      LAYER M2 ;
      RECT 67.985 202.790 68.055 203.000 ;
    END
  END rw0_rd_out[80]
  PIN rw0_rd_out[81]
    DIRECTION OUTPUT ;
    USE SIGNAL ;
    SHAPE ABUTMENT ;
    PORT
      LAYER M2 ;
      RECT 70.075 202.790 70.145 203.000 ;
    END
  END rw0_rd_out[81]
  PIN rw0_rd_out[82]
    DIRECTION OUTPUT ;
    USE SIGNAL ;
    SHAPE ABUTMENT ;
    PORT
      LAYER M2 ;
      RECT 72.165 202.790 72.235 203.000 ;
    END
  END rw0_rd_out[82]
  PIN rw0_rd_out[83]
    DIRECTION OUTPUT ;
    USE SIGNAL ;
    SHAPE ABUTMENT ;
    PORT
      LAYER M2 ;
      RECT 74.255 202.790 74.325 203.000 ;
    END
  END rw0_rd_out[83]
  PIN rw0_rd_out[84]
    DIRECTION OUTPUT ;
    USE SIGNAL ;
    SHAPE ABUTMENT ;
    PORT
      LAYER M2 ;
      RECT 76.345 202.790 76.415 203.000 ;
    END
  END rw0_rd_out[84]
  PIN rw0_rd_out[85]
    DIRECTION OUTPUT ;
    USE SIGNAL ;
    SHAPE ABUTMENT ;
    PORT
      LAYER M2 ;
      RECT 78.435 202.790 78.505 203.000 ;
    END
  END rw0_rd_out[85]
  PIN rw0_rd_out[86]
    DIRECTION OUTPUT ;
    USE SIGNAL ;
    SHAPE ABUTMENT ;
    PORT
      LAYER M2 ;
      RECT 80.525 202.790 80.595 203.000 ;
    END
  END rw0_rd_out[86]
  PIN rw0_rd_out[87]
    DIRECTION OUTPUT ;
    USE SIGNAL ;
    SHAPE ABUTMENT ;
    PORT
      LAYER M2 ;
      RECT 82.615 202.790 82.685 203.000 ;
    END
  END rw0_rd_out[87]
  PIN rw0_rd_out[88]
    DIRECTION OUTPUT ;
    USE SIGNAL ;
    SHAPE ABUTMENT ;
    PORT
      LAYER M2 ;
      RECT 84.705 202.790 84.775 203.000 ;
    END
  END rw0_rd_out[88]
  PIN rw0_rd_out[89]
    DIRECTION OUTPUT ;
    USE SIGNAL ;
    SHAPE ABUTMENT ;
    PORT
      LAYER M2 ;
      RECT 86.795 202.790 86.865 203.000 ;
    END
  END rw0_rd_out[89]
  PIN rw0_rd_out[90]
    DIRECTION OUTPUT ;
    USE SIGNAL ;
    SHAPE ABUTMENT ;
    PORT
      LAYER M2 ;
      RECT 88.885 202.790 88.955 203.000 ;
    END
  END rw0_rd_out[90]
  PIN rw0_rd_out[91]
    DIRECTION OUTPUT ;
    USE SIGNAL ;
    SHAPE ABUTMENT ;
    PORT
      LAYER M2 ;
      RECT 90.975 202.790 91.045 203.000 ;
    END
  END rw0_rd_out[91]
  PIN rw0_rd_out[92]
    DIRECTION OUTPUT ;
    USE SIGNAL ;
    SHAPE ABUTMENT ;
    PORT
      LAYER M2 ;
      RECT 93.065 202.790 93.135 203.000 ;
    END
  END rw0_rd_out[92]
  PIN rw0_rd_out[93]
    DIRECTION OUTPUT ;
    USE SIGNAL ;
    SHAPE ABUTMENT ;
    PORT
      LAYER M2 ;
      RECT 95.155 202.790 95.225 203.000 ;
    END
  END rw0_rd_out[93]
  PIN rw0_rd_out[94]
    DIRECTION OUTPUT ;
    USE SIGNAL ;
    SHAPE ABUTMENT ;
    PORT
      LAYER M2 ;
      RECT 97.245 202.790 97.315 203.000 ;
    END
  END rw0_rd_out[94]
  PIN rw0_addr_in[0]
    DIRECTION INPUT ;
    USE SIGNAL ;
    SHAPE ABUTMENT ;
    PORT
      LAYER M3 ;
      RECT 0.000 172.165 0.210 172.235 ;
    END
  END rw0_addr_in[0]
  PIN rw0_addr_in[1]
    DIRECTION INPUT ;
    USE SIGNAL ;
    SHAPE ABUTMENT ;
    PORT
      LAYER M3 ;
      RECT 0.000 179.305 0.210 179.375 ;
    END
  END rw0_addr_in[1]
  PIN rw0_addr_in[2]
    DIRECTION INPUT ;
    USE SIGNAL ;
    SHAPE ABUTMENT ;
    PORT
      LAYER M3 ;
      RECT 0.000 186.445 0.210 186.515 ;
    END
  END rw0_addr_in[2]
  PIN rw0_addr_in[3]
    DIRECTION INPUT ;
    USE SIGNAL ;
    SHAPE ABUTMENT ;
    PORT
      LAYER M3 ;
      RECT 0.000 193.585 0.210 193.655 ;
    END
  END rw0_addr_in[3]
  PIN rw0_addr_in[4]
    DIRECTION INPUT ;
    USE SIGNAL ;
    SHAPE ABUTMENT ;
    PORT
      LAYER M3 ;
      RECT 115.880 172.165 116.090 172.235 ;
    END
  END rw0_addr_in[4]
  PIN rw0_addr_in[5]
    DIRECTION INPUT ;
    USE SIGNAL ;
    SHAPE ABUTMENT ;
    PORT
      LAYER M3 ;
      RECT 115.880 179.305 116.090 179.375 ;
    END
  END rw0_addr_in[5]
  PIN rw0_addr_in[6]
    DIRECTION INPUT ;
    USE SIGNAL ;
    SHAPE ABUTMENT ;
    PORT
      LAYER M3 ;
      RECT 115.880 186.445 116.090 186.515 ;
    END
  END rw0_addr_in[6]
  PIN rw0_addr_in[7]
    DIRECTION INPUT ;
    USE SIGNAL ;
    SHAPE ABUTMENT ;
    PORT
      LAYER M3 ;
      RECT 115.880 193.585 116.090 193.655 ;
    END
  END rw0_addr_in[7]
  PIN rw0_we_in
    DIRECTION INPUT ;
    USE SIGNAL ;
    SHAPE ABUTMENT ;
    PORT
      LAYER M2 ;
      RECT 99.335 202.790 99.405 203.000 ;
    END
  END rw0_we_in
  PIN rw0_ce_in
    DIRECTION INPUT ;
    USE SIGNAL ;
    SHAPE ABUTMENT ;
    PORT
      LAYER M2 ;
      RECT 101.425 202.790 101.495 203.000 ;
    END
  END rw0_ce_in
  PIN rw0_clk
    DIRECTION INPUT ;
    USE SIGNAL ;
    SHAPE ABUTMENT ;
    PORT
      LAYER M2 ;
      RECT 103.515 202.790 103.585 203.000 ;
    END
  END rw0_clk
  PIN VSS
    DIRECTION INOUT ;
    USE GROUND ;
    PORT
      LAYER M4 ;
      RECT 1.000 0.840 1.280 202.160 ;
      RECT 3.240 0.840 3.520 202.160 ;
      RECT 5.480 0.840 5.760 202.160 ;
      RECT 7.720 0.840 8.000 202.160 ;
      RECT 9.960 0.840 10.240 202.160 ;
      RECT 12.200 0.840 12.480 202.160 ;
      RECT 14.440 0.840 14.720 202.160 ;
      RECT 16.680 0.840 16.960 202.160 ;
      RECT 18.920 0.840 19.200 202.160 ;
      RECT 21.160 0.840 21.440 202.160 ;
      RECT 23.400 0.840 23.680 202.160 ;
      RECT 25.640 0.840 25.920 202.160 ;
      RECT 27.880 0.840 28.160 202.160 ;
      RECT 30.120 0.840 30.400 202.160 ;
      RECT 32.360 0.840 32.640 202.160 ;
      RECT 34.600 0.840 34.880 202.160 ;
      RECT 36.840 0.840 37.120 202.160 ;
      RECT 39.080 0.840 39.360 202.160 ;
      RECT 41.320 0.840 41.600 202.160 ;
      RECT 43.560 0.840 43.840 202.160 ;
      RECT 45.800 0.840 46.080 202.160 ;
      RECT 48.040 0.840 48.320 202.160 ;
      RECT 50.280 0.840 50.560 202.160 ;
      RECT 52.520 0.840 52.800 202.160 ;
      RECT 54.760 0.840 55.040 202.160 ;
      RECT 57.000 0.840 57.280 202.160 ;
      RECT 59.240 0.840 59.520 202.160 ;
      RECT 61.480 0.840 61.760 202.160 ;
      RECT 63.720 0.840 64.000 202.160 ;
      RECT 65.960 0.840 66.240 202.160 ;
      RECT 68.200 0.840 68.480 202.160 ;
      RECT 70.440 0.840 70.720 202.160 ;
      RECT 72.680 0.840 72.960 202.160 ;
      RECT 74.920 0.840 75.200 202.160 ;
      RECT 77.160 0.840 77.440 202.160 ;
      RECT 79.400 0.840 79.680 202.160 ;
      RECT 81.640 0.840 81.920 202.160 ;
      RECT 83.880 0.840 84.160 202.160 ;
      RECT 86.120 0.840 86.400 202.160 ;
      RECT 88.360 0.840 88.640 202.160 ;
      RECT 90.600 0.840 90.880 202.160 ;
      RECT 92.840 0.840 93.120 202.160 ;
      RECT 95.080 0.840 95.360 202.160 ;
      RECT 97.320 0.840 97.600 202.160 ;
      RECT 99.560 0.840 99.840 202.160 ;
      RECT 101.800 0.840 102.080 202.160 ;
      RECT 104.040 0.840 104.320 202.160 ;
      RECT 106.280 0.840 106.560 202.160 ;
      RECT 108.520 0.840 108.800 202.160 ;
      RECT 110.760 0.840 111.040 202.160 ;
      RECT 113.000 0.840 113.280 202.160 ;
      RECT 115.240 0.840 115.520 202.160 ;
    END
  END VSS
  PIN VDD
    DIRECTION INOUT ;
    USE POWER ;
    PORT
      LAYER M4 ;
      RECT 1.000 0.840 1.280 202.160 ;
      RECT 3.240 0.840 3.520 202.160 ;
      RECT 5.480 0.840 5.760 202.160 ;
      RECT 7.720 0.840 8.000 202.160 ;
      RECT 9.960 0.840 10.240 202.160 ;
      RECT 12.200 0.840 12.480 202.160 ;
      RECT 14.440 0.840 14.720 202.160 ;
      RECT 16.680 0.840 16.960 202.160 ;
      RECT 18.920 0.840 19.200 202.160 ;
      RECT 21.160 0.840 21.440 202.160 ;
      RECT 23.400 0.840 23.680 202.160 ;
      RECT 25.640 0.840 25.920 202.160 ;
      RECT 27.880 0.840 28.160 202.160 ;
      RECT 30.120 0.840 30.400 202.160 ;
      RECT 32.360 0.840 32.640 202.160 ;
      RECT 34.600 0.840 34.880 202.160 ;
      RECT 36.840 0.840 37.120 202.160 ;
      RECT 39.080 0.840 39.360 202.160 ;
      RECT 41.320 0.840 41.600 202.160 ;
      RECT 43.560 0.840 43.840 202.160 ;
      RECT 45.800 0.840 46.080 202.160 ;
      RECT 48.040 0.840 48.320 202.160 ;
      RECT 50.280 0.840 50.560 202.160 ;
      RECT 52.520 0.840 52.800 202.160 ;
      RECT 54.760 0.840 55.040 202.160 ;
      RECT 57.000 0.840 57.280 202.160 ;
      RECT 59.240 0.840 59.520 202.160 ;
      RECT 61.480 0.840 61.760 202.160 ;
      RECT 63.720 0.840 64.000 202.160 ;
      RECT 65.960 0.840 66.240 202.160 ;
      RECT 68.200 0.840 68.480 202.160 ;
      RECT 70.440 0.840 70.720 202.160 ;
      RECT 72.680 0.840 72.960 202.160 ;
      RECT 74.920 0.840 75.200 202.160 ;
      RECT 77.160 0.840 77.440 202.160 ;
      RECT 79.400 0.840 79.680 202.160 ;
      RECT 81.640 0.840 81.920 202.160 ;
      RECT 83.880 0.840 84.160 202.160 ;
      RECT 86.120 0.840 86.400 202.160 ;
      RECT 88.360 0.840 88.640 202.160 ;
      RECT 90.600 0.840 90.880 202.160 ;
      RECT 92.840 0.840 93.120 202.160 ;
      RECT 95.080 0.840 95.360 202.160 ;
      RECT 97.320 0.840 97.600 202.160 ;
      RECT 99.560 0.840 99.840 202.160 ;
      RECT 101.800 0.840 102.080 202.160 ;
      RECT 104.040 0.840 104.320 202.160 ;
      RECT 106.280 0.840 106.560 202.160 ;
      RECT 108.520 0.840 108.800 202.160 ;
      RECT 110.760 0.840 111.040 202.160 ;
      RECT 113.000 0.840 113.280 202.160 ;
      RECT 115.240 0.840 115.520 202.160 ;
    END
  END VDD
  OBS
    LAYER M1 ;
    RECT 0 0 116.090 203.000 ;
    LAYER M2 ;
    RECT 0 0 116.090 203.000 ;
    LAYER M3 ;
    RECT 0 0 116.090 203.000 ;
    LAYER M4 ;
    RECT 0 0 116.090 203.000 ;
    LAYER OVERLAP ;
    RECT 0 0 116.090 203.000 ;
  END
END ht45_blackparrot_256x95_bottom

END LIBRARY
